VERSION 5.7 ;
BUSBITCHARS "[]" ;
DIVIDERCHAR "/" ;

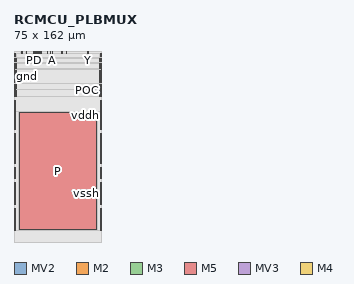
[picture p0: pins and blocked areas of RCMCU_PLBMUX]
MACRO RCMCU_PLBMUX
  CLASS BLOCK ;
  ORIGIN 0 0 ;
  FOREIGN RCMCU_PLBMUX 0 0 ;
  SIZE 75 BY 162 ;
  SYMMETRY X Y R90 ;
  PIN A
    DIRECTION INPUT ;
    USE SIGNAL ;
    PORT
      LAYER MV2 ;
        RECT 32.645 160.885 32.835 161.075 ;
        RECT 32.645 161.405 32.835 161.595 ;
    END
    PORT
      LAYER M2 ;
        RECT 32.49 160.79 32.99 162 ;
    END
    PORT
      LAYER M3 ;
        RECT 32.49 160.79 32.99 162 ;
    END
  END A
  PIN CS
    DIRECTION INPUT ;
    USE SIGNAL ;
    PORT
      LAYER MV2 ;
        RECT 44.685 161.405 44.875 161.595 ;
        RECT 44.685 160.885 44.875 161.075 ;
    END
    PORT
      LAYER M2 ;
        RECT 44.53 160.79 45.03 162 ;
    END
    PORT
      LAYER M3 ;
        RECT 44.53 160.79 45.03 162 ;
    END
  END CS
  PIN DR
    DIRECTION INPUT ;
    USE SIGNAL ;
    PORT
      LAYER MV2 ;
        RECT 23.505 160.885 23.695 161.075 ;
        RECT 23.505 161.405 23.695 161.595 ;
    END
    PORT
      LAYER M2 ;
        RECT 23.35 160.79 23.85 162 ;
    END
    PORT
      LAYER M3 ;
        RECT 23.35 160.79 23.85 162 ;
    END
  END DR
  PIN IE
    DIRECTION INPUT ;
    USE SIGNAL ;
    PORT
      LAYER MV2 ;
        RECT 40.885 161.405 41.075 161.595 ;
        RECT 40.885 160.885 41.075 161.075 ;
    END
    PORT
      LAYER M2 ;
        RECT 40.73 160.79 41.23 162 ;
    END
    PORT
      LAYER M3 ;
        RECT 40.73 160.79 41.23 162 ;
    END
  END IE
  PIN OD
    DIRECTION INPUT ;
    USE SIGNAL ;
    PORT
      LAYER MV2 ;
        RECT 28.585 161.405 28.775 161.595 ;
        RECT 28.585 160.885 28.775 161.075 ;
    END
    PORT
      LAYER M2 ;
        RECT 28.43 160.79 28.93 162 ;
    END
    PORT
      LAYER M3 ;
        RECT 28.43 160.79 28.93 162 ;
    END
  END OD
  PIN OE
    DIRECTION INPUT ;
    USE SIGNAL ;
    PORT
      LAYER MV2 ;
        RECT 31.105 161.405 31.295 161.595 ;
        RECT 31.105 160.885 31.295 161.075 ;
    END
    PORT
      LAYER M2 ;
        RECT 30.95 160.79 31.45 162 ;
    END
    PORT
      LAYER M3 ;
        RECT 30.95 160.79 31.45 162 ;
    END
  END OE
  PIN OS
    DIRECTION INPUT ;
    USE SIGNAL ;
    PORT
      LAYER MV2 ;
        RECT 21.855 160.885 22.045 161.075 ;
        RECT 21.855 161.405 22.045 161.595 ;
    END
    PORT
      LAYER M2 ;
        RECT 21.7 160.79 22.2 162 ;
    END
    PORT
      LAYER M3 ;
        RECT 21.7 160.79 22.2 162 ;
    END
  END OS
  PIN P
    DIRECTION INOUT ;
    USE SIGNAL ;
    PORT
      LAYER M5 ;
        RECT 4.5 10.5 70.5 110.5 ;
    END
  END P
  PIN PD
    DIRECTION INPUT ;
    USE SIGNAL ;
    PORT
      LAYER MV2 ;
        RECT 17.065 160.885 17.255 161.075 ;
        RECT 17.065 161.405 17.255 161.595 ;
    END
    PORT
      LAYER M2 ;
        RECT 16.91 160.79 17.41 162 ;
    END
    PORT
      LAYER M3 ;
        RECT 16.91 160.79 17.41 162 ;
    END
  END PD
  PIN POC
    DIRECTION OUTPUT ;
    USE POWER ;
    PORT
      LAYER MV2 ;
        RECT 6.655 160.905 6.845 161.095 ;
    END
    PORT
      LAYER MV2 ;
        RECT 6.655 161.385 6.845 161.575 ;
    END
    PORT
      LAYER M3 ;
        RECT 6.06 160.79 6.96 162 ;
    END
    PORT
      LAYER MV2 ;
        RECT 6.175 160.905 6.365 161.095 ;
    END
    PORT
      LAYER MV2 ;
        RECT 6.175 161.385 6.365 161.575 ;
    END
    PORT
      LAYER M2 ;
        RECT 6.06 160.79 6.96 162 ;
    END
    PORT
      LAYER M3 ;
        RECT 0 129.1 1.28 130 ;
    END
    PORT
      LAYER M3 ;
        RECT 73.72 129.1 75 130 ;
    END
  END POC
  PIN PU
    DIRECTION INPUT ;
    USE SIGNAL ;
    PORT
      LAYER MV2 ;
        RECT 18.605 161.405 18.795 161.595 ;
        RECT 18.605 160.885 18.795 161.075 ;
    END
    PORT
      LAYER M2 ;
        RECT 18.45 160.79 18.95 162 ;
    END
    PORT
      LAYER M3 ;
        RECT 18.45 160.79 18.95 162 ;
    END
  END PU
  PIN SR
    DIRECTION INPUT ;
    USE SIGNAL ;
    PORT
      LAYER MV2 ;
        RECT 20.315 160.885 20.505 161.075 ;
        RECT 20.315 161.405 20.505 161.595 ;
    END
    PORT
      LAYER M2 ;
        RECT 20.16 160.79 20.66 162 ;
    END
    PORT
      LAYER M3 ;
        RECT 20.16 160.79 20.66 162 ;
    END
  END SR
  PIN Y
    DIRECTION OUTPUT ;
    USE SIGNAL ;
    PORT
      LAYER MV2 ;
        RECT 62.955 161.405 63.145 161.595 ;
        RECT 62.955 160.885 63.145 161.075 ;
    END
    PORT
      LAYER M2 ;
        RECT 62.8 160.79 63.3 162 ;
    END
    PORT
      LAYER M3 ;
        RECT 62.8 160.79 63.3 162 ;
    END
  END Y
  PIN YA
    DIRECTION INOUT ;
    USE SIGNAL ;
    PORT
      LAYER MV2 ;
        RECT 10.425 160.885 10.615 161.075 ;
        RECT 10.425 161.405 10.615 161.595 ;
    END
    PORT
      LAYER M2 ;
        RECT 10.27 160.79 10.77 162 ;
    END
    PORT
      LAYER M3 ;
        RECT 10.27 160.79 10.77 162 ;
    END
  END YA
  PIN gnd
    DIRECTION INOUT ;
    USE GROUND ;
    PORT
      LAYER MV3 ;
        RECT 73.6 158.44 73.79 158.63 ;
        RECT 74.21 158.44 74.4 158.63 ;
        RECT 73.6 159.05 73.79 159.24 ;
        RECT 74.21 159.05 74.4 159.24 ;
        RECT 73.6 159.66 73.79 159.85 ;
        RECT 74.21 159.66 74.4 159.85 ;
        RECT 0.6 158.44 0.79 158.63 ;
        RECT 1.21 158.44 1.4 158.63 ;
        RECT 0.6 159.05 0.79 159.24 ;
        RECT 1.21 159.05 1.4 159.24 ;
        RECT 0.6 159.66 0.79 159.85 ;
        RECT 1.21 159.66 1.4 159.85 ;
    END
    PORT
      LAYER M3 ;
        RECT 73.415 157.97 75 160.37 ;
    END
    PORT
      LAYER M3 ;
        RECT 0 157.97 1.585 160.37 ;
    END
    PORT
      LAYER M3 ;
        RECT 0 59.66 1.28 63.66 ;
    END
    PORT
      LAYER M3 ;
        RECT 73.72 59.66 75 63.66 ;
    END
    PORT
      LAYER M4 ;
        RECT 73.415 157.97 75 160.47 ;
    END
    PORT
      LAYER M4 ;
        RECT 0 157.97 1.585 160.47 ;
    END
    PORT
      LAYER M4 ;
        RECT 0 135.99 2 146.46 ;
    END
    PORT
      LAYER M4 ;
        RECT 73 135.99 75 146.46 ;
    END
    PORT
      LAYER M5 ;
        RECT 73.415 157.97 75 160.47 ;
    END
    PORT
      LAYER M5 ;
        RECT 0 157.97 1.585 160.47 ;
    END
    PORT
      LAYER M5 ;
        RECT 0 135.99 1.585 146.46 ;
    END
    PORT
      LAYER M5 ;
        RECT 73.415 135.99 75 146.46 ;
    END
  END gnd
  PIN vdd
    DIRECTION INOUT ;
    USE POWER ;
    PORT
      LAYER M4 ;
        RECT 0 153.8 2 156.3 ;
    END
    PORT
      LAYER M4 ;
        RECT 73 153.8 75 156.3 ;
    END
    PORT
      LAYER M5 ;
        RECT 0 153.8 1.585 156.3 ;
    END
    PORT
      LAYER M5 ;
        RECT 73.415 153.8 75 156.3 ;
    END
  END vdd
  PIN vddh
    DIRECTION INOUT ;
    USE POWER ;
    PORT
      LAYER M3 ;
        RECT 74.4 137.66 75 150.47 ;
    END
    PORT
      LAYER M3 ;
        RECT 0 137.66 0.6 150.47 ;
    END
    PORT
      LAYER M3 ;
        RECT 73.72 95.54 75 120.85 ;
    END
    PORT
      LAYER M3 ;
        RECT 0 95.54 1.28 120.85 ;
    END
    PORT
      LAYER M3 ;
        RECT 0 66.96 1.28 92.24 ;
    END
    PORT
      LAYER M3 ;
        RECT 73.72 66.96 75 92.24 ;
    END
    PORT
      LAYER M3 ;
        RECT 0 53.99 1.28 57.99 ;
    END
    PORT
      LAYER M3 ;
        RECT 73.72 53.99 75 57.99 ;
    END
    PORT
      LAYER M4 ;
        RECT 0 130.82 2 134.32 ;
    END
    PORT
      LAYER M4 ;
        RECT 73 130.82 75 134.32 ;
    END
    PORT
      LAYER M5 ;
        RECT 0 130.82 1.585 134.32 ;
    END
    PORT
      LAYER M5 ;
        RECT 73.415 130.82 75 134.32 ;
    END
  END vddh
  PIN vssh
    DIRECTION INOUT ;
    USE GROUND ;
    PORT
      LAYER M3 ;
        RECT 73.72 31.95 75 50.69 ;
    END
    PORT
      LAYER M3 ;
        RECT 0 31.95 1.28 50.69 ;
    END
    PORT
      LAYER M3 ;
        RECT 0 9.91 1.28 28.65 ;
    END
    PORT
      LAYER M3 ;
        RECT 73.72 9.91 75 28.65 ;
    END
    PORT
      LAYER M4 ;
        RECT 73 148.13 75 152.13 ;
    END
    PORT
      LAYER M4 ;
        RECT 0 148.13 2 152.13 ;
    END
    PORT
      LAYER M4 ;
        RECT 0 124.15 2 129.15 ;
    END
    PORT
      LAYER M4 ;
        RECT 73 124.15 75 129.15 ;
    END
    PORT
      LAYER M5 ;
        RECT 73.415 148.13 75 152.13 ;
    END
    PORT
      LAYER M5 ;
        RECT 0 148.13 1.585 152.13 ;
    END
    PORT
      LAYER M5 ;
        RECT 0 124.15 1.585 129.15 ;
    END
    PORT
      LAYER M5 ;
        RECT 73.415 124.15 75 129.15 ;
    END
  END vssh
  OBS
    LAYER GATE ;
      RECT 0 0 75 162 ;
    LAYER MV1 ;
      RECT 0 0 75 162 ;
    LAYER MV2 ;
      RECT 0 0 75 162 ;
    LAYER MV3 ;
      RECT 0 0 75 162 ;
    LAYER MV4 ;
      RECT 0 0 75 162 ;
    LAYER M1 ;
      RECT 0 0 75 162 ;
    LAYER M2 ;
      RECT 0 0 75 160.55 ;
      RECT 11.01 160.55 16.67 162 ;
      RECT 17.65 160.55 18.21 162 ;
      RECT 19.19 160.55 19.92 162 ;
      RECT 20.9 160.55 21.46 162 ;
      RECT 22.44 160.55 23.11 162 ;
      RECT 24.09 160.55 28.19 162 ;
      RECT 29.17 160.55 30.71 162 ;
      RECT 31.69 160.55 32.25 162 ;
      RECT 33.23 160.55 40.49 162 ;
      RECT 41.47 160.55 44.29 162 ;
      RECT 45.27 160.55 62.56 162 ;
      RECT 63.54 160.55 75 162 ;
    LAYER M3 ;
      RECT 7.2 160.55 10.03 160.61 ;
    LAYER M2 ;
      RECT 7.2 160.55 10.03 162 ;
    LAYER M3 ;
      RECT 11.01 160.55 16.67 162 ;
      RECT 17.65 160.55 18.21 162 ;
      RECT 19.19 160.55 19.92 162 ;
      RECT 20.9 160.55 21.46 162 ;
      RECT 22.44 160.55 23.11 162 ;
      RECT 24.09 160.55 28.19 162 ;
      RECT 29.17 160.55 30.71 162 ;
      RECT 31.69 160.55 32.25 162 ;
      RECT 33.23 160.55 40.49 162 ;
      RECT 41.47 160.55 44.29 162 ;
      RECT 45.27 160.55 62.56 162 ;
      RECT 1.825 157.73 73.175 160.55 ;
      RECT 63.54 160.61 75 162 ;
      RECT 63.54 160.55 73.175 160.61 ;
      RECT 1.88 94.94 73.12 121.45 ;
      RECT 1.88 31.35 73.12 51.29 ;
      RECT 1.88 9.31 73.12 29.25 ;
      RECT 1.88 66.36 73.12 92.84 ;
      RECT 0 151.07 75 157.73 ;
      RECT 1.52 128.86 73.48 130.24 ;
      RECT 1.52 59.42 73.48 63.9 ;
      RECT 1.52 53.75 73.48 58.23 ;
      RECT 0 130.24 75 137.06 ;
      RECT 1.2 137.06 73.8 151.07 ;
      RECT 0 121.45 75 128.86 ;
      RECT 0 92.84 75 94.94 ;
      RECT 0 58.23 75 59.42 ;
      RECT 0 63.9 75 66.36 ;
      RECT 0 51.29 75 53.75 ;
      RECT 0 29.25 75 31.35 ;
      RECT 0 0 75 9.31 ;
    LAYER M4 ;
      RECT 0 0 75 123.91 ;
      RECT 0 129.39 75 130.58 ;
      RECT 2.24 123.91 72.76 129.39 ;
      RECT 2.6 135.39 72.4 147.06 ;
      RECT 0 134.56 75 135.39 ;
      RECT 2.24 130.58 72.76 134.56 ;
      RECT 0 147.06 75 147.89 ;
      RECT 0 152.37 75 153.56 ;
      RECT 2.24 147.89 72.76 152.37 ;
      RECT 0 156.54 75 157.73 ;
      RECT 2.24 153.56 72.76 156.54 ;
      RECT 0 160.71 75 162 ;
      RECT 1.825 157.73 73.175 160.71 ;
    LAYER M5 ;
      RECT 0 9.9 3.9 111.1 ;
      RECT 71.1 9.9 75 111.1 ;
      RECT 0 0 75 9.9 ;
      RECT 0 111.1 75 123.69 ;
      RECT 0 129.61 75 130.36 ;
      RECT 2.045 123.69 72.955 129.61 ;
      RECT 2.185 135.39 72.815 147.06 ;
      RECT 0 134.78 75 135.39 ;
      RECT 2.045 130.36 72.955 134.78 ;
      RECT 0 147.06 75 147.67 ;
      RECT 0 152.59 75 153.34 ;
      RECT 2.045 147.67 72.955 152.59 ;
      RECT 0 156.76 75 157.51 ;
      RECT 2.045 153.34 72.955 156.76 ;
      RECT 0 160.93 75 162 ;
      RECT 2.045 157.51 72.955 160.93 ;
    LAYER M3 ;
      RECT 7.2 160.61 10.03 162 ;
      RECT 0 160.61 5.82 162 ;
      RECT 1.825 160.55 5.82 160.61 ;
    LAYER M2 ;
      RECT 0 160.55 5.82 162 ;
  END
END RCMCU_PLBMUX

END LIBRARY
